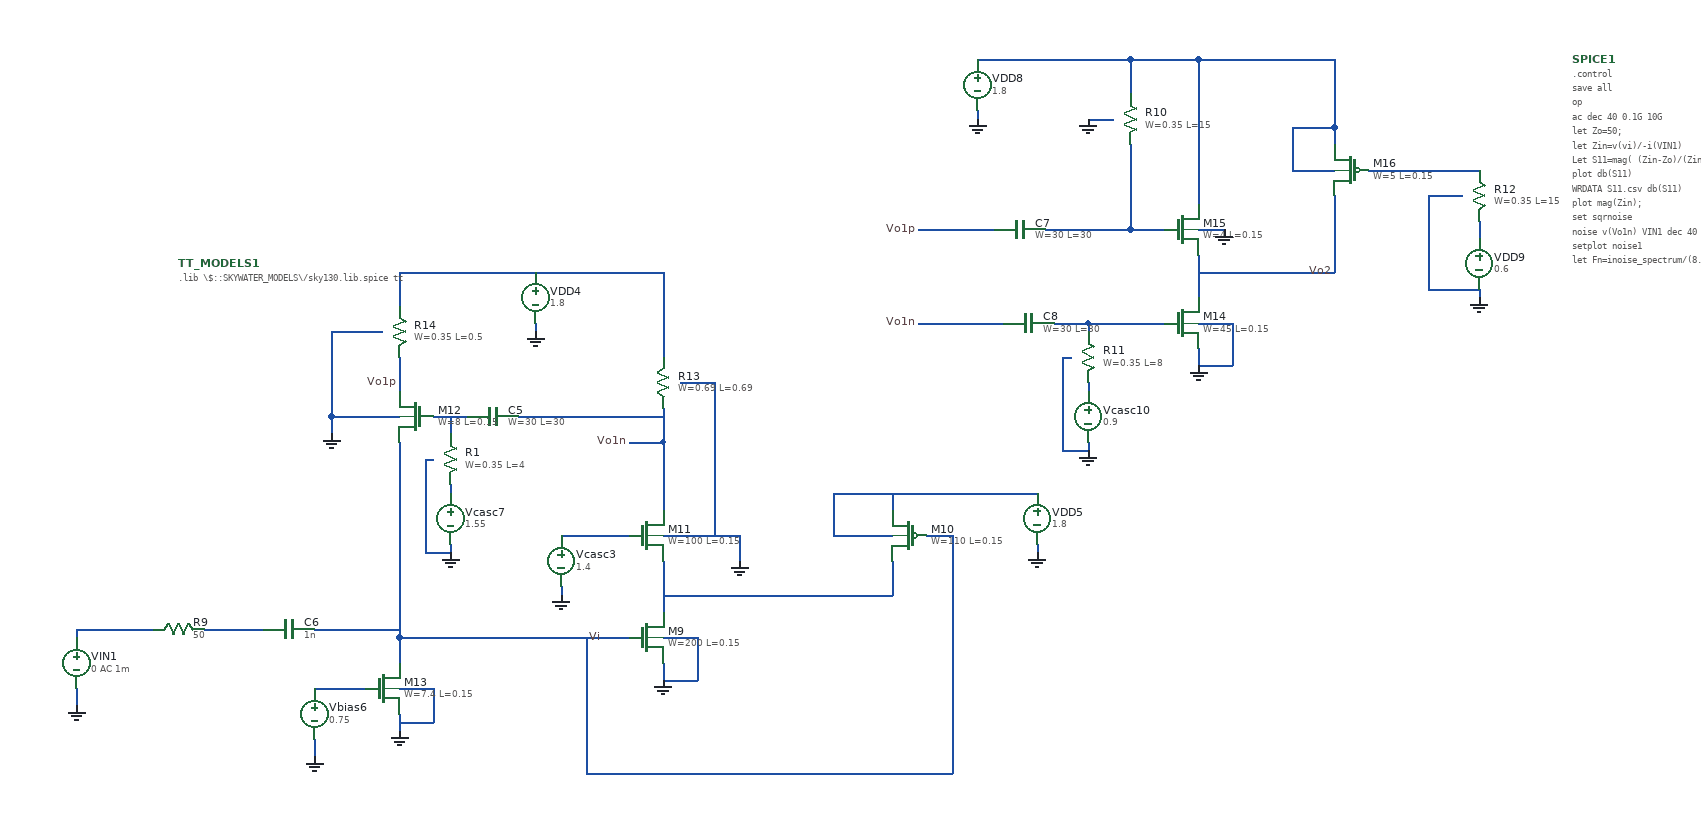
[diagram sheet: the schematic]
v {xschem version=3.0.0 file_version=1.2 }
G {}
K {}
V {}
S {}
E {}
N 1770 -1780 1810 -1780 { lab=GND}
N 1810 -1780 1810 -1730 { lab=GND}
N 1770 -1730 1810 -1730 { lab=GND}
N 1770 -1750 1770 -1730 { lab=GND}
N 1770 -1870 1770 -1810 { lab=#net1}
N 1690 -1780 1730 -1780 { lab=Vi}
N 1770 -1900 1860 -1900 { lab=GND}
N 1860 -1900 1860 -1870 { lab=GND}
N 1690 -1900 1730 -1900 { lab=#net2}
N 1770 -1960 1770 -1930 { lab=Vo1n}
N 1770 -2040 1770 -2010 { lab=Vo1n}
N 1650 -1900 1690 -1900 { lab=#net2}
N 1630 -1780 1690 -1780 { lab=Vi}
N 1650 -1840 1650 -1830 { lab=GND}
N 1080 -1720 1080 -1700 { lab=GND}
N 1620 -2210 1660 -2210 { lab=#net3}
N 1620 -2150 1620 -2140 { lab=GND}
N 1770 -2150 1770 -2110 { lab=#net3}
N 1660 -2210 1770 -2210 { lab=#net3}
N 1730 -2010 1770 -2010 { lab=Vo1n}
N 2040 -1870 2040 -1830 { lab=#net1}
N 1770 -1830 2040 -1830 { lab=#net1}
N 2170 -1950 2210 -1950 { lab=#net4}
N 2210 -1890 2210 -1880 { lab=GND}
N 2040 -1950 2040 -1930 { lab=#net4}
N 2040 -1950 2170 -1950 { lab=#net4}
N 2080 -1900 2110 -1900 { lab=#net4}
N 1970 -1900 2040 -1900 { lab=#net4}
N 1970 -1950 1970 -1900 { lab=#net4}
N 1970 -1950 2050 -1950 { lab=#net4}
N 1830 -2020 1830 -1900 { lab=GND}
N 1460 -1690 1460 -1670 { lab=GND}
N 1460 -1720 1500 -1720 { lab=GND}
N 1500 -1720 1500 -1680 { lab=GND}
N 1460 -1680 1500 -1680 { lab=GND}
N 1460 -1780 1460 -1750 { lab=Vi}
N 1540 -1780 1630 -1780 { lab=Vi}
N 1080 -1790 1080 -1780 { lab=#net5}
N 1790 -2080 1830 -2080 { lab=GND}
N 1830 -2080 1830 -2020 { lab=GND}
N 1770 -2050 1770 -2030 { lab=Vo1n}
N 1770 -2010 1770 -1960 { lab=Vo1n}
N 1360 -1720 1420 -1720 { lab=#net6}
N 1360 -1660 1360 -1640 { lab=GND}
N 1460 -1780 1540 -1780 { lab=Vi}
N 1460 -1920 1460 -1780 { lab=Vi}
N 1460 -1990 1460 -1920 { lab=Vi}
N 1380 -2040 1460 -2040 { lab=GND}
N 1380 -2040 1380 -2020 { lab=GND}
N 1770 -2210 1770 -2150 { lab=#net3}
N 1520 -1890 1520 -1880 { lab=GND}
N 1520 -1960 1520 -1950 { lab=#net7}
N 1490 -1990 1500 -1990 { lab=GND}
N 1490 -1990 1490 -1880 { lab=GND}
N 1490 -1880 1520 -1880 { lab=GND}
N 1460 -2010 1460 -1990 { lab=Vi}
N 1500 -2040 1540 -2040 { lab=#net8}
N 1520 -2040 1520 -2020 { lab=#net8}
N 1600 -2040 1670 -2040 { lab=Vo1n}
N 1670 -2040 1770 -2040 { lab=Vo1n}
N 1460 -2110 1460 -2070 { lab=Vo1p}
N 1380 -2140 1440 -2140 { lab=GND}
N 1380 -2140 1380 -2040 { lab=GND}
N 1460 -2210 1460 -2170 { lab=#net3}
N 1460 -2210 1620 -2210 { lab=#net3}
N 1230 -1790 1300 -1790 { lab=#net9}
N 1360 -1790 1460 -1790 { lab=Vi}
N 1080 -1790 1170 -1790 { lab=#net5}
N 2270 -2390 2300 -2390 { lab=GND}
N 2320 -2260 2360 -2260 { lab=#net10}
N 2320 -2360 2320 -2260 { lab=#net10}
N 2400 -2460 2400 -2290 { lab=#net11}
N 2320 -2460 2400 -2460 { lab=#net11}
N 2320 -2460 2320 -2420 { lab=#net11}
N 2400 -2230 2400 -2180 { lab=Vo2}
N 2400 -2260 2430 -2260 { lab=GND}
N 2560 -2300 2560 -2210 { lab=Vo2}
N 2400 -2210 2560 -2210 { lab=Vo2}
N 2510 -2330 2560 -2330 { lab=#net11}
N 2510 -2380 2510 -2330 { lab=#net11}
N 2510 -2380 2560 -2380 { lab=#net11}
N 2560 -2380 2560 -2360 { lab=#net11}
N 2560 -2460 2560 -2380 { lab=#net11}
N 2400 -2460 2560 -2460 { lab=#net11}
N 2600 -2330 2630 -2330 { lab=#net12}
N 2140 -2400 2140 -2390 { lab=GND}
N 2140 -2460 2320 -2460 { lab=#net11}
N 2730 -2190 2730 -2180 { lab=GND}
N 2620 -2330 2670 -2330 { lab=#net12}
N 2400 -2150 2440 -2150 { lab=GND}
N 2440 -2150 2440 -2100 { lab=GND}
N 2400 -2100 2440 -2100 { lab=GND}
N 2400 -2120 2400 -2100 { lab=GND}
N 2220 -2260 2320 -2260 { lab=#net10}
N 2070 -2260 2160 -2260 { lab=Vo1p}
N 2270 -2010 2270 -2000 { lab=GND}
N 2270 -2080 2270 -2070 { lab=#net13}
N 2240 -2110 2250 -2110 { lab=GND}
N 2240 -2110 2240 -2000 { lab=GND}
N 2240 -2000 2270 -2000 { lab=GND}
N 2270 -2150 2270 -2140 { lab=#net14}
N 2270 -2150 2360 -2150 { lab=#net14}
N 2230 -2150 2270 -2150 { lab=#net14}
N 2070 -2150 2170 -2150 { lab=Vo1n}
N 2670 -2330 2730 -2330 { lab=#net12}
N 2730 -2270 2730 -2250 { lab=#net15}
N 2670 -2300 2710 -2300 { lab=GND}
N 2670 -2300 2670 -2200 { lab=GND}
N 2670 -2200 2670 -2190 { lab=GND}
N 2670 -2190 2730 -2190 { lab=GND}
N 2110 -1900 2110 -1620 {}
N 1680 -1620 2110 -1620 {}
N 1680 -1780 1680 -1620 {}
C {devices/code.sym} 1200 -2220 0 0 {name=TT_MODELS1
spice_ignore=false
only_toplevel=true
format="tcleval( @value )"
value="
.lib \\\\$::SKYWATER_MODELS\\\\/sky130.lib.spice tt
"}
C {devices/code_shown.sym} 2840 -2460 0 0 {name=SPICE1 spice_ignore=false only_toplevel=true value="

.control
save all
op

ac dec 40 0.1G 10G

let Zo=50;
let Zin=v(vi)/-i(VIN1)
Let S11=mag( (Zin-Zo)/(Zin+Zo) )
plot db(S11)
WRDATA S11.csv db(S11)
plot mag(Zin);


set sqrnoise

noise v(Vo1n) VIN1 dec 40 1G 10G
setplot noise1
let Fn=inoise_spectrum/(8.3e-19)
let NFn=db(Fn) / 2
plot NFn

WRData Noise.csv NF2

.endc
"}
C {devices/gnd.sym} 1770 -1730 0 0 {name=l22 lab=GND}
C {devices/gnd.sym} 1860 -1870 0 0 {name=l24 lab=GND}
C {devices/vsource.sym} 1080 -1750 0 0 {name=VIN1 value="0 AC 1m"}
C {devices/vsource.sym} 1650 -1870 0 0 {name=Vcasc3 value=1.4}
C {devices/gnd.sym} 1080 -1700 0 0 {name=l25 lab=GND}
C {devices/gnd.sym} 1650 -1830 0 0 {name=l26 lab=GND}
C {devices/vsource.sym} 1620 -2180 0 0 {name=VDD4 value=1.8}
C {devices/gnd.sym} 1620 -2140 0 0 {name=l27 lab=GND}
C {devices/lab_wire.sym} 1730 -2010 0 0 {name=l28 sig_type=std_logic lab=Vo1n}
C {devices/lab_wire.sym} 1700 -1780 0 0 {name=l29 sig_type=std_logic lab=Vi}
C {devices/vsource.sym} 2210 -1920 0 1 {name=VDD5 value=1.8}
C {devices/gnd.sym} 2210 -1880 0 1 {name=l30 lab=GND}
C {devices/gnd.sym} 1460 -1670 0 0 {name=l31 lab=GND}
C {devices/vsource.sym} 1360 -1690 0 0 {name=Vbias6 value=0.75}
C {devices/gnd.sym} 1360 -1640 0 0 {name=l32 lab=GND}
C {devices/gnd.sym} 1380 -2020 0 0 {name=l33 lab=GND}
C {devices/vsource.sym} 1520 -1920 0 0 {name=Vcasc7 value=1.55}
C {devices/gnd.sym} 1520 -1880 0 0 {name=l34 lab=GND}
C {sky130_fd_pr/res_high_po_0p35.sym} 1520 -1990 0 0 {name=R1
W=0.35
L=4
model=res_high_po_0p35
spiceprefix=X
mult=1}
C {sky130_fd_pr/cap_mim_m3_2.sym} 1570 -2040 3 0 {name=C5 model=cap_mim_m3_2 W=30 L=30 MF=1 spiceprefix=X}
C {devices/capa.sym} 1330 -1790 3 0 {name=C6
m=1
value=1n
footprint=1206
device="ceramic capacitor"}
C {devices/lab_wire.sym} 1460 -2080 0 0 {name=l35 sig_type=std_logic lab=Vo1p}
C {sky130_fd_pr/nfet_01v8_lvt.sym} 1750 -1780 0 0 {name=M9
L=0.15
W=200
nf=20
mult=1
ad="'int((nf+1)/2) * W/nf * 0.29'" 
pd="'2*int((nf+1)/2) * (W/nf + 0.29)'"
as="'int((nf+2)/2) * W/nf * 0.29'" 
ps="'2*int((nf+2)/2) * (W/nf + 0.29)'"
nrd="'0.29 / W'" nrs="'0.29 / W'"
sa=0 sb=0 sd=0
model=nfet_01v8_lvt
spiceprefix=X
}
C {sky130_fd_pr/pfet_01v8.sym} 2060 -1900 0 1 {name=M10
L=0.15
W=110
nf=11
mult=1
ad="'int((nf+1)/2) * W/nf * 0.29'" 
pd="'2*int((nf+1)/2) * (W/nf + 0.29)'"
as="'int((nf+2)/2) * W/nf * 0.29'" 
ps="'2*int((nf+2)/2) * (W/nf + 0.29)'"
nrd="'0.29 / W'" nrs="'0.29 / W'"
sa=0 sb=0 sd=0
model=pfet_01v8
spiceprefix=X
}
C {sky130_fd_pr/nfet_01v8_lvt.sym} 1750 -1900 0 0 {name=M11
L=0.15
W=100
nf=10
mult=1
ad="'int((nf+1)/2) * W/nf * 0.29'" 
pd="'2*int((nf+1)/2) * (W/nf + 0.29)'"
as="'int((nf+2)/2) * W/nf * 0.29'" 
ps="'2*int((nf+2)/2) * (W/nf + 0.29)'"
nrd="'0.29 / W'" nrs="'0.29 / W'"
sa=0 sb=0 sd=0
model=nfet_01v8_lvt
spiceprefix=X
}
C {sky130_fd_pr/nfet_01v8_lvt.sym} 1480 -2040 0 1 {name=M12
L=0.15
W=8
nf=1
mult=1
ad="'int((nf+1)/2) * W/nf * 0.29'" 
pd="'2*int((nf+1)/2) * (W/nf + 0.29)'"
as="'int((nf+2)/2) * W/nf * 0.29'" 
ps="'2*int((nf+2)/2) * (W/nf + 0.29)'"
nrd="'0.29 / W'" nrs="'0.29 / W'"
sa=0 sb=0 sd=0
model=nfet_01v8_lvt
spiceprefix=X
}
C {sky130_fd_pr/nfet_01v8_lvt.sym} 1440 -1720 0 0 {name=M13
L=0.15
W=7.4
nf=1
mult=1
ad="'int((nf+1)/2) * W/nf * 0.29'" 
pd="'2*int((nf+1)/2) * (W/nf + 0.29)'"
as="'int((nf+2)/2) * W/nf * 0.29'" 
ps="'2*int((nf+2)/2) * (W/nf + 0.29)'"
nrd="'0.29 / W'" nrs="'0.29 / W'"
sa=0 sb=0 sd=0
model=nfet_01v8_lvt
spiceprefix=X
}
C {devices/res.sym} 1200 -1790 3 0 {name=R9
value=50
footprint=1206
device=resistor
m=1}
C {sky130_fd_pr/nfet_01v8_lvt.sym} 2380 -2150 0 0 {name=M14
L=0.15
W=45
nf=9
mult=1
ad="'int((nf+1)/2) * W/nf * 0.29'" 
pd="'2*int((nf+1)/2) * (W/nf + 0.29)'"
as="'int((nf+2)/2) * W/nf * 0.29'" 
ps="'2*int((nf+2)/2) * (W/nf + 0.29)'"
nrd="'0.29 / W'" nrs="'0.29 / W'"
sa=0 sb=0 sd=0
model=nfet_01v8_lvt
spiceprefix=X
}
C {sky130_fd_pr/nfet_01v8_lvt.sym} 2380 -2260 0 0 {name=M15
L=0.15
W=4
nf=1
mult=3
ad="'int((nf+1)/2) * W/nf * 0.29'" 
pd="'2*int((nf+1)/2) * (W/nf + 0.29)'"
as="'int((nf+2)/2) * W/nf * 0.29'" 
ps="'2*int((nf+2)/2) * (W/nf + 0.29)'"
nrd="'0.29 / W'" nrs="'0.29 / W'"
sa=0 sb=0 sd=0
model=nfet_01v8_lvt
spiceprefix=X
}
C {sky130_fd_pr/res_high_po_0p35.sym} 2320 -2390 0 0 {name=R10
W=0.35
L=15
model=res_high_po_0p35
spiceprefix=X
mult=1}
C {devices/gnd.sym} 2270 -2390 0 0 {name=l36 lab=GND}
C {sky130_fd_pr/pfet_01v8.sym} 2580 -2330 0 1 {name=M16
L=0.15
W=5
nf=1
mult=16
ad="'int((nf+1)/2) * W/nf * 0.29'" 
pd="'2*int((nf+1)/2) * (W/nf + 0.29)'"
as="'int((nf+2)/2) * W/nf * 0.29'" 
ps="'2*int((nf+2)/2) * (W/nf + 0.29)'"
nrd="'0.29 / W'" nrs="'0.29 / W'"
sa=0 sb=0 sd=0
model=pfet_01v8
spiceprefix=X
}
C {devices/vsource.sym} 2140 -2430 0 1 {name=VDD8 value=1.8}
C {devices/gnd.sym} 2140 -2390 0 1 {name=l37 lab=GND}
C {devices/vsource.sym} 2730 -2220 0 1 {name=VDD9 value=0.6}
C {devices/gnd.sym} 2730 -2180 0 1 {name=l38 lab=GND}
C {devices/gnd.sym} 2430 -2260 0 1 {name=l39 lab=GND}
C {sky130_fd_pr/cap_mim_m3_2.sym} 2190 -2260 3 0 {name=C7 model=cap_mim_m3_2 W=30 L=30 MF=1 spiceprefix=X}
C {devices/gnd.sym} 2400 -2100 0 1 {name=l40 lab=GND}
C {devices/vsource.sym} 2270 -2040 0 0 {name=Vcasc10 value=0.9}
C {devices/gnd.sym} 2270 -2000 0 0 {name=l41 lab=GND}
C {sky130_fd_pr/res_high_po_0p35.sym} 2270 -2110 0 0 {name=R11
W=0.35
L=8
model=res_high_po_0p35
spiceprefix=X
mult=1}
C {sky130_fd_pr/cap_mim_m3_2.sym} 2200 -2150 3 0 {name=C8 model=cap_mim_m3_2 W=30 L=30 MF=1 spiceprefix=X}
C {devices/lab_wire.sym} 2070 -2260 0 0 {name=l42 sig_type=std_logic lab=Vo1p}
C {devices/lab_wire.sym} 2070 -2150 0 0 {name=l43 sig_type=std_logic lab=Vo1n}
C {sky130_fd_pr/res_high_po_0p35.sym} 2730 -2300 0 0 {name=R12
W=0.35
L=15
model=res_high_po_0p35
spiceprefix=X
mult=1}
C {devices/lab_wire.sym} 2560 -2210 0 0 {name=l44 sig_type=std_logic lab=Vo2}
C {sky130_fd_pr/res_high_po_0p69.sym} 1770 -2080 0 1 {name=R13
W=0.69
L=0.69
model=res_high_po_0p69
spiceprefix=X
mult=4}
C {sky130_fd_pr/res_high_po_0p35.sym} 1460 -2140 0 0 {name=R14
W=0.35
L=0.5
model=res_high_po_0p35
spiceprefix=X
mult=1}
